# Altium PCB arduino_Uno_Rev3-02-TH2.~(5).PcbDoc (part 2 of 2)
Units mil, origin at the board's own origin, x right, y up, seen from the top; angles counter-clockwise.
Board outline 3492.03 x 2110.03 mil, 2 copper layers (Top Layer, Bottom Layer); 62 components, 73 nets, 317 pads, 75 vias.

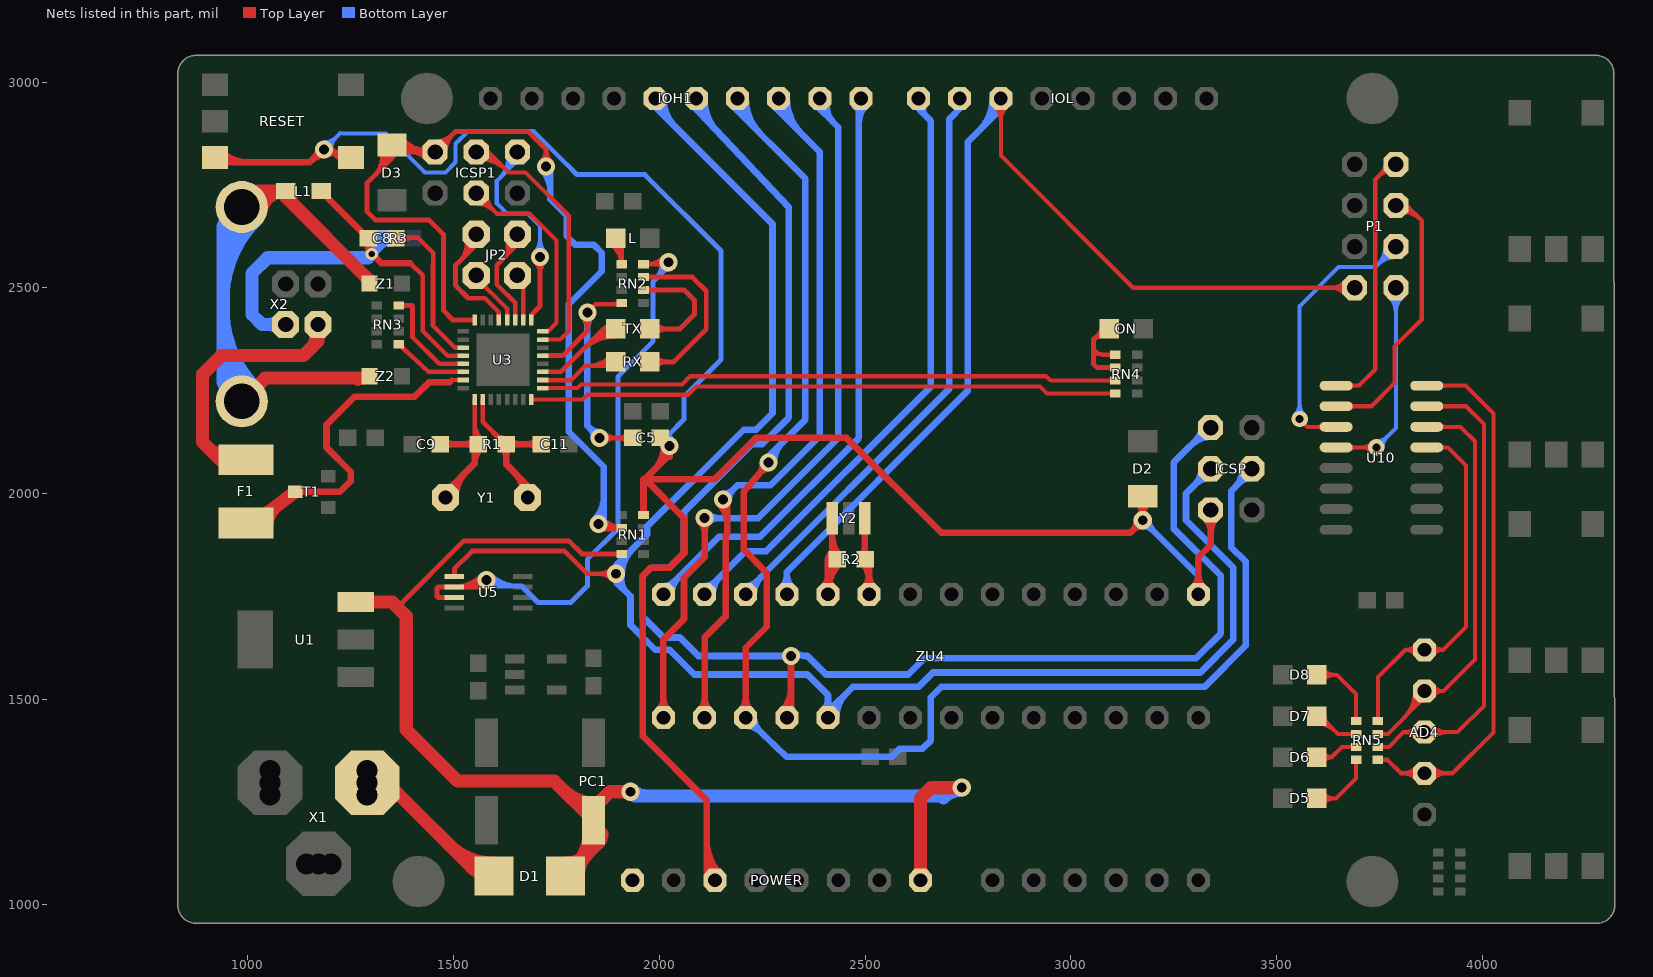
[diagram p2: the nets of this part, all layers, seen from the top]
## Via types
v1: diameter 44, hole 24, Top Layer to Bottom Layer, 62 vias
v2: diameter 30, hole 15, Top Layer to Bottom Layer, 10 vias
v3: diameter 40, hole 20, Top Layer to Bottom Layer, 2 vias
v4: diameter 50, hole 28, Top Layer to Bottom Layer, 1 vias

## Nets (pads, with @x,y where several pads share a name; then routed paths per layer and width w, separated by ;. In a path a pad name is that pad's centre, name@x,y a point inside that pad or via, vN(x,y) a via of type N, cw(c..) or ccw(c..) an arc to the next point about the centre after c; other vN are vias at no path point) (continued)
IO5: IOL.6 P1.7 ZU4.11 | length 3062.7
  Top Layer w10: IOL.6@2813.74,2943.74 cw(c2774.47,2904.47) 2830,2904.47 cw(c2885.53,2904.47) IOL.6@2846.26,2943.74 ; IOL.6@2820.81,2950.81 cw(c2798.62,2928.62) 2830,2928.62 cw(c2861.38,2928.62) IOL.6@2839.19,2950.81 ; IOL.6@2830,2960 2830,2821 3151,2500 P1.7@3690,2500 ; P1.7@3671.96,2481.96 ccw(c3628.41,2438.41) 3628.41,2500 ccw(c3628.41,2561.59) P1.7@3671.96,2518.04 ; P1.7@3679.03,2489.03 ccw(c3652.55,2462.55) 3652.55,2500 ccw(c3652.55,2537.45) P1.7@3679.03,2510.97
  Bottom Layer w16: ZU4.11@2295.86,1769.14 ccw(c2261.72,1803.28) 2310,1803.28 ccw(c2358.28,1803.28) ZU4.11@2324.14,1769.14 ; ZU4.11@2310,1755 2310,1810 2750,2250 2750,2855 2835,2940 IOL.6@2835,2960 ; 2778.18,2883.18 ccw(c2701.36,2960) IOL.6@2810,2960 ; 2805.49,2910.49 ccw(c2755.99,2960) IOL.6@2826,2960
IO6: IOL.7 ZU4.12 | length 1498.3
  Bottom Layer w16: ZU4.12@2210,1755 2210,1760 2705,2255 2705,2910 2735,2940 IOL.7@2735,2960 ; ZU4.12@2210,1775 ccw(c2210,1811.21) 2235.61,1785.61 ; ZU4.12@2230,1755 cw(c2290.36,1755) 2247.68,1797.68
IO7: IOL.8 ZU4.13 | length 1611.2
  Bottom Layer w16: ZU4.13@2110,1755 2110,1760 2210,1860 2260,1860 2660,2260 2660,2905 2635,2930 IOL.8@2635,2960 ; ZU4.13@2110,1775 ccw(c2110,1811.21) 2135.61,1785.61 ; ZU4.13@2130,1755 cw(c2190.36,1755) 2147.68,1797.68 ; IOL.8@2633.14,2957.53 ccw(c2649.31,2944.79) 2634.76,2930.24 ; IOL.8@2645.71,2947.63 ccw(c2663.57,2933.57) 2647.5,2917.5
IO8: IOH1.1 ZU4.14 | length 1636.2
  Bottom Layer w16: ZU4.14@2010,1755 2010,1760 2145,1895 2245,1895 2485,2135 2485,2950 2475,2940 IOH1.1@2475,2960 ; ZU4.14@2010,1775 ccw(c2010,1811.21) 2035.61,1785.61 ; ZU4.14@2030,1755 cw(c2090.36,1755) 2047.68,1797.68 ; IOH1.1@2475.86,2945.86 cw(c2453.79,2923.79) 2485,2923.79 ; 2485,2899.64 cw(c2550.36,2899.64) IOH1.1@2504.14,2945.86
IO9: IOH1.2 ZU4.15 | length 2060.7
  Top Layer w16: ZU4.15@1995.86,1469.14 ccw(c1961.72,1503.28) 2010,1503.28 ccw(c2058.28,1503.28) ZU4.15@2024.14,1469.14 ; ZU4.15@2010,1455 2010,1645 2060,1695 2060,1795 2110,1845 v1(2110,1940) ; v1@2100.1,1930.1 cw(c2076.2,1906.2) 2110,1906.2 cw(c2143.8,1906.2) v1@2119.9,1930.1
  Bottom Layer w16: v1(2110,1940) 2240,1940 2435,2135 2435,2890 2375,2950 IOH1.2@2375,2960 ; v1@2119.9,1930.1 cw(c2143.8,1906.2) 2143.8,1940 cw(c2143.8,1973.8) v1@2119.9,1949.9 ; IOH1.2@2393.84,2958.88 ccw(c2430.09,2948.31) 2403.39,2921.61 ; IOH1.2@2409.2,2954.4 ccw(c2459.68,2939.68) 2422.5,2902.5
L13: RN2.8 U5.6 U5.7 | length 1884.4
  Top Layer w12: U5.7@1501.85,1747.17 1462.83,1747.17 1460,1750 1460,1770 1462.76,1772.76 U5.6@1501.85,1772.76 ; 1530.07,1772.76 ccw(c1530.07,1838.08) v1@1577.12,1792.77 ; 1558.28,1772.76 ccw(c1558.28,1810.91) v1@1585.76,1784.45 ; v1@1568.47,1801.1 cw(c1501.85,1865.24) U5.6@1501.85,1772.76 ; v1(1580,1790) 1565,1775 1562.76,1772.76 U5.6@1501.85,1772.76 ; RN2.8@1961.57,2557.24 2027.24,2557.24 2032,2562 v1(2022,2562) ; RN2.8@1971.88,2557.24 ccw(c1971.88,2612.12) v1@2010.69,2573.31 ; 1994.86,2557.24 cw(c1994.86,2534.86) v1@2010.69,2550.69
  Bottom Layer w12: v1@1574.34,1784.34 ccw(c1596.9,1806.9) 1596.9,1775 ; v1(1580,1790) 1595,1775 1665,1775 1705,1735 1785,1735 1825,1775 1825,1840 1900,1915 1900,2285 1985,2370 1985,2515 2032,2562 v1(2022,2562) ; v1@1582.83,1792.83 ccw(c1625.87,1835.87) 1625.87,1775 ; v1@1591.31,1801.31 ccw(c1654.84,1864.84) 1654.84,1775 ; 1990,2520 ccw(c1951.21,2558.8) v1@2006.02,2561.28 ; 2009.25,2539.25 ccw(c1988.03,2560.46) v1@2018,2561.82 ; 2011.76,2541.76 cw(c2022,2531.51) v1@2022,2546
M8RXD: RN4.7 U3.9 | length 1426.8
  Top Layer w10: U3.9@1716.46,2256.1 1801.1,2256.1 1810,2265 2055,2265 2075,2285 2940,2285 2950.75,2274.25 RN4.7@3108.43,2274.25 ; RN4.7@3102.05,2270.83 ccw(c3093.79,2262.56) 3093.79,2274.25 ccw(c3093.79,2285.94) RN4.7@3102.05,2277.67
M8TXD: RN4.8 U3.8 | length 1458.1
  Top Layer w10: U3.8@1688.9,2228.54 1813.54,2228.54 1825,2240 2070,2240 2090,2260 2925,2260 2942.24,2242.76 RN4.8@3108.43,2242.76 ; RN4.8@3102.05,2239.34 ccw(c3093.79,2231.07) 3093.79,2242.76 ccw(c3093.79,2254.45) RN4.8@3102.05,2246.18
MISO: ICSP.1 IOH1.5 ZU4.18 | length 4098
  Top Layer w16: ZU4.18@2295.86,1469.14 ccw(c2237.57,1527.43) 2320,1527.43 ; ZU4.18@2307.17,1457.83 ccw(c2276.2,1488.8) 2320,1488.8 ; ZU4.18@2310,1455 2320,1465 v1(2320,1605)
  Bottom Layer w16: IOH1.5@2075,2950 IOH1.5@2075,2960 ; IOH1.5@2077.05,2947.82 2315,2695 2315,2185 2250,2120 2225,2120 2060,1955 2060,1855 2025,1820 1980,1820 1960,1800 1960,1700 2010,1650 2050,1650 2095,1605 v1(2320,1605) ; IOH1.5@2094,2959.88 ccw(c2164.32,2957.75) 2113.09,2909.53 ; IOH1.5@2109.99,2959.39 ccw(c2218.92,2956.09) 2139.56,2881.4 ; v1@2329.9,1614.9 ccw(c2353.8,1638.8) 2353.8,1605 ; 2360,1605 2405,1560 2605,1560 2645,1600 3305,1600 3365,1660 3365,1800 3250,1915 3250,2075 3333.03,2158.03 ICSP.1@3340,2160 ; 3293.03,2118.03 cw(c3340,2071.07) ICSP.1@3340,2137.49 ; 3305.11,2130.11 ccw(c3275.21,2160) ICSP.1@3317.49,2160
MISO2: ICSP1.1 U3.17 | length 921.2
  Top Layer w10: v1@1697.98,2562.98 cw(c1668.96,2533.96) 1710,2533.96 cw(c1751.04,2533.96) v1@1722.02,2562.98 ; 1710,2515 v1(1710,2575)
  Top Layer w11: U3.17@1688.9,2421.46 1688.9,2433.9 1695,2440 ; U3.17@1688.91,2429.73 cw(c1699.01,2429.73) 1691.87,2436.87
  Top Layer w12: 1695,2440 1710,2455 v1(1710,2575) ; v1@1698.69,2563.69 cw(c1671.37,2536.37) 1710,2536.37 cw(c1748.63,2536.37) v1@1721.31,2563.69
  Bottom Layer w10: 1615,2770 ccw(c1574.45,2810.56) ICSP1.1@1630.2,2824.01 ; 1627.61,2782.61 ccw(c1594.76,2815.46) ICSP1.1@1639.92,2826.36 ; 1640.22,2795.22 ccw(c1615.07,2820.36) ICSP1.1@1649.64,2828.71 ; ICSP1.1@1645.59,2800.59 cw(c1655,2791.18) ICSP1.1@1655,2804.49 ; ICSP1.1@1655,2830 1655,2810 1605,2760 1605,2705 1630,2680 1680,2680 1710,2650 v1(1710,2575) ; v1@1697.98,2587.02 ccw(c1668.96,2616.04) 1710,2616.04 ccw(c1751.04,2616.04) v1@1722.02,2587.02
MOSI: ICSP.4 IOH1.4 ZU4.17 | length 4138.3
  Top Layer w16: ZU4.17@2195.86,1469.14 ccw(c2161.72,1503.28) 2210,1503.28 ccw(c2258.28,1503.28) ZU4.17@2224.14,1469.14 ; ZU4.17@2210,1455 2210,1625 2261,1676 2261,1807 2205,1865 2205,2005 2215,2015 v1(2265,2075) ; v1@2251.06,2073.73 cw(c2217.4,2070.67) 2243.36,2049.03 cw(c2269.33,2027.4) v1@2266.27,2061.06
  Bottom Layer w15: 3390,1869 3390,2006
  Bottom Layer w16: IOH1.4@2175,2960 2175,2945 2355,2765 2355,2180 2265,2090 v1(2265,2075) ; IOH1.4@2178,2960 ccw(c2221.46,2960) 2190.73,2929.27 ; IOH1.4@2194,2960 ccw(c2276.08,2960) 2218.04,2901.96 ; ZU4.17@2210,1455 2310,1360 2565,1360 2585,1380 2640,1380 2660,1400 2660,1505 2685,1530 3325,1530 3425,1630 3425,1835 3390,1869 ; IOH1.4@2210,2960 ccw(c2330.71,2960) 2245.36,2874.64 ; ZU4.17@2210.51,1435.01 cw(c2211.75,1386.74) 2245.01,1421.74 cw(c2278.26,1456.75) ZU4.17@2229.99,1455.51 ; v1@2263,2075 cw(c2294.38,2075) 2272.19,2097.19 ; v1@2279,2075 cw(c2349.01,2075) 2299.51,2124.51 ; 3390,2006 3440.51,2055.51 ICSP.4@3440,2060 ; 3397.54,2013.39 ccw(c3350.98,2060.89) ICSP.4@3417.49,2060.23 ; 3409.83,2025.43 cw(c3439.35,1995.31) ICSP.4@3439.77,2037.49
MOSI2: ICSP1.4 U3.16 | length 649.4
  Top Layer w10: ICSP1.4@1555,2704.49 cw(c1555,2642.9) 1598.55,2686.45 cw(c1642.1,2730) ICSP1.4@1580.51,2730 ; ICSP1.4@1555,2714.49 cw(c1555,2677.04) 1581.48,2703.52 cw(c1607.96,2730) ICSP1.4@1570.51,2730 ; ICSP1.4@1555,2730 1605,2680 1685,2680 1750,2615 1750,2415 1728.9,2393.9 U3.16@1716.46,2393.9 ; U3.16@1724.73,2394.41 ccw(c1724.73,2405.72) 1732.72,2397.72
NetC5_1: C5.1 RN2.4 U3.13 | length 966
  Top Layer w10: v1(1825,2440) 1845,2460 RN2.4@1905.67,2460 ; 1887.12,2460 ccw(c1887.12,2481.11) RN2.4@1902.05,2466.18
  Top Layer w12: U3.13@1716.46,2334.84 1764.84,2334.84 1825,2395 v1(1825,2440) ; v1@1813.69,2428.69 cw(c1786.37,2401.37) 1825,2401.37 cw(c1863.63,2401.37) v1@1836.31,2428.69 ; v1@1866.31,2123.69 cw(c1893.63,2096.37) 1893.63,2135 cw(c1893.63,2173.63) v1@1866.31,2146.31 ; v1@1875,2135 C5.1@1935,2135 ; RN2.4@1905.67,2460 RN2.4@1908.43,2462.76 ; C5.1@1923.85,2125.1 ccw(c1899.95,2101.2) 1899.95,2135 ccw(c1899.95,2168.8) C5.1@1923.85,2144.9
  Top Layer w16: v1(1855,2135) v1@1875,2135
  Bottom Layer w16: v1@1815.1,2430.1 cw(c1791.2,2406.2) 1825,2406.2 cw(c1858.8,2406.2) v1@1834.9,2430.1 ; v1(1825,2440) 1825,2165 v1(1855,2135) ; v1@1841,2135 ccw(c1807.2,2135) 1831.1,2158.9 ccw(c1855,2182.8) v1@1855,2149
NetD5_C: D5.C RN5.8 | length 249.5
  Top Layer w10: D5.C@3598.34,1259 3645,1259 3693.43,1307.43 RN5.8@3693.43,1352.76 ; D5.C@3611.51,1245.83 cw(c3643.3,1214.04) 3643.3,1259 cw(c3643.3,1303.96) D5.C@3611.51,1272.17 ; RN5.8@3690.01,1349.34 cw(c3681.74,1341.07) 3693.43,1341.07 cw(c3705.12,1341.07) RN5.8@3696.85,1349.34
NetD6_C: D6.C RN5.7 | length 171.7
  Top Layer w10: D6.C@3598.34,1359 3634,1359 ; D6.C@3613.62,1348.36 cw(c3634,1334.17) 3634,1359 ; D6.C@3613.62,1369.64 ccw(c3634,1383.83) 3634,1359 ; RN5.7@3687.05,1380.83 ccw(c3678.79,1372.56) 3678.79,1384.25 ccw(c3678.79,1395.94) RN5.7@3687.05,1387.67 ; RN5.7@3693.43,1384.25 3659.25,1384.25 3634,1359
NetD7_C: D7.C RN5.6 | length 232.9
  Top Layer w10: D7.C@3598.34,1440.38 cw(c3598.34,1376.93) 3643.21,1421.79 ; D7.C@3598.34,1450.38 cw(c3598.34,1411.07) 3626.14,1438.86 ; D7.C@3598.34,1459 3606,1459 3649.25,1415.75 RN5.6@3693.43,1415.75 ; D7.C@3616.96,1459 ccw(c3643.43,1459) 3624.71,1440.29 ; RN5.6@3687.05,1412.33 ccw(c3678.79,1404.06) 3678.79,1415.75 ccw(c3678.79,1427.44) RN5.6@3687.05,1419.17
NetD8_C: D8.C RN5.5 | length 268.6
  Top Layer w10: D8.C@3598.34,1559 3647,1559 3693.43,1512.57 RN5.5@3693.43,1447.24 ; D8.C@3611.51,1545.83 cw(c3643.3,1514.04) 3643.3,1559 cw(c3643.3,1603.96) D8.C@3611.51,1572.17 ; RN5.5@3690.01,1450.66 ccw(c3681.74,1458.93) 3693.43,1458.93 ccw(c3705.12,1458.93) RN5.5@3696.85,1450.66
NetL_A: L.A RN2.1 | length 235.1
  Top Layer w11: L.A@1883.02,2605.33 cw(c1846.92,2555.53) RN2.1@1908.43,2555.53 ; L.A@1889.48,2614.23 cw(c1862.55,2577.09) 1908.43,2577.09 ; L.A@1893.66,2620 1885,2620 1908.43,2596.57 RN2.1@1908.43,2557.24 RN2.1@1900.76,2557.24 ; L.A@1895.94,2623.14 cw(c1878.18,2598.65) L.A@1908.43,2598.65 ; RN2.1@1905.36,2560.31 ccw(c1897.95,2567.72) 1908.43,2567.72 ccw(c1918.91,2567.72) RN2.1@1911.5,2560.31
NetON_A: ON.A RN4.5 RN4.6 | length 288
  Top Layer w12: ON.A@3076.43,2403.7 cw(c3034.83,2412.62) 3057.94,2376.9 cw(c3081.04,2341.17) ON.A@3089.96,2382.77 ; ON.A@3093.66,2400 3055,2375 3055,2350 ; RN4.6@3108.43,2305.75 3064.25,2305.75 3055,2315 3055,2350 ; RN4.5@3108.43,2337.24 3077.76,2337.24 3065,2340 3055,2350
NetP1_2: P1.2 U10.1 | length 762.2
  Top Layer w10: U10.1@3645,2262 3701,2262 3740,2301 3740,2763 3777,2800 P1.2@3790,2800 ; U10.1@3677.95,2257.05 cw(c3689.9,2245.1) 3689.9,2262 cw(c3689.9,2278.9) U10.1@3677.95,2266.95 ; 3747.91,2770.91 cw(c3781.93,2736.89) P1.2@3788.03,2784.61 ; 3755.64,2778.64 ccw(c3734.28,2800) P1.2@3764.49,2800 ; P1.2@3762.32,2785.32 cw(c3785.2,2762.43) P1.2@3789.3,2794.53
NetP1_4: P1.4 U10.2 | length 870.3
  Top Layer w10: U10.2@3645,2212 3731,2212 3787,2268 3787,2357 3853,2423 3853,2663 3816,2700 P1.4@3790,2700 ; U10.2@3677.95,2207.05 cw(c3689.9,2195.1) 3689.9,2212 cw(c3689.9,2228.9) U10.2@3677.95,2216.95 ; P1.4@3789.42,2704.45 cw(c3794.62,2664.73) 3822.94,2693.06 ; P1.4@3790.72,2694.53 cw(c3797.94,2639.35) 3837.29,2678.71 ; P1.4@3792.01,2684.62 cw(c3801.26,2613.97) 3851.65,2664.35
  Bottom Layer w10: P1.4@3765,2700 P1.4@3790,2700
NetP1_6: P1.6 U10.3 | length 921.3
  Top Layer w10: v3(3556,2181) 3575,2162 U10.3@3645,2162 ; U10.3@3612.05,2157.05 ccw(c3600.1,2145.1) 3600.1,2162 ccw(c3600.1,2178.9) U10.3@3612.05,2166.95
  Bottom Layer w10: v3@3545.39,2191.61 ccw(c3519.79,2217.21) 3556,2217.21 ccw(c3592.21,2217.21) v3@3566.61,2191.61 ; v3(3556,2181) 3555,2181 3556,2182 3556,2455 3651,2550 3740,2550 P1.6@3790,2600 P1.6@3774,2600 ; P1.6@3764.49,2600 cw(c3702.9,2600) 3746.45,2556.45 cw(c3790,2512.9) P1.6@3790,2574.49 ; P1.6@3774.49,2600 cw(c3737.04,2600) 3763.52,2573.52 cw(c3790,2547.04) P1.6@3790,2584.49
NetP1_8: P1.8 U10.4 | length 801.4
  Top Layer w10: U10.4@3645,2112 v3(3743,2112) ; U10.4@3677.95,2107.05 cw(c3689.9,2095.1) 3689.9,2112 cw(c3689.9,2128.9) U10.4@3677.95,2116.95 ; v3@3732.39,2101.39 ccw(c3706.79,2075.79) 3706.79,2112 ccw(c3706.79,2148.21) v3@3732.39,2122.61
  Bottom Layer w10: v3(3743,2112) 3790,2159 P1.8@3790,2500 ; v3@3743,2127 ccw(c3743,2163.21) 3768.61,2137.61 ccw(c3794.21,2112) v3@3758,2112 ; P1.8@3771.96,2481.96 cw(c3728.41,2438.41) 3790,2438.41 cw(c3851.59,2438.41) P1.8@3808.04,2481.96 ; P1.8@3779.03,2489.03 cw(c3752.55,2462.55) 3790,2462.55 cw(c3827.45,2462.55) P1.8@3800.97,2489.03
NetPOWER_1: POWER.1
NetRN2_6: RN2.6 TX.A | length 358.6
  Top Layer w12: RN2.6@1961.57,2494.25 2060.75,2494.25 2070,2485 2085,2470 2085,2435 2049.76,2399.76 1986.57,2399.76 TX.A@1976.34,2400 ; TX.A@1988.8,2387.54 cw(c2018.3,2358.04) 2018.3,2399.76 ; TX.A@1988.8,2412.46 ccw(c2019.46,2443.12) 2019.46,2399.76
NetRN2_7: RN2.7 RX.A | length 496.6
  Top Layer w12: RN2.7@1961.57,2525.75 2080.25,2525.75 2114,2492 2114,2399 2035,2320 RX.A@1976.34,2320 ; RX.A@1988.8,2307.54 cw(c2018.88,2277.46) 2018.88,2320 cw(c2018.88,2362.54) RX.A@1988.8,2332.46
OUT1: AD4.2 RN5.1 U10.16 | length 1618.1
  Top Layer w10: RN5.1@3746.57,1352.76 3770.24,1352.76 3803,1320 AD4.2@3860,1320 3928,1320 4027,1419 4027,2194 3959,2262 U10.16@3865,2262 ; RN5.1@3752.95,1349.34 cw(c3761.21,1341.07) 3761.21,1352.76 cw(c3761.21,1364.45) RN5.1@3752.95,1356.18 ; AD4.2@3843.74,1303.74 ccw(c3804.47,1264.47) 3804.47,1320 ccw(c3804.47,1375.53) AD4.2@3843.74,1336.26 ; AD4.2@3850.81,1310.81 ccw(c3828.62,1288.62) 3828.62,1320 ccw(c3828.62,1351.38) AD4.2@3850.81,1329.19 ; AD4.2@3869.19,1310.81 cw(c3891.38,1288.62) 3891.38,1320 cw(c3891.38,1351.38) AD4.2@3869.19,1329.19 ; AD4.2@3876.26,1303.74 cw(c3915.53,1264.47) 3915.53,1320 cw(c3915.53,1375.53) AD4.2@3876.26,1336.26 ; U10.16@3897.95,2257.05 cw(c3909.9,2245.1) 3909.9,2262 cw(c3909.9,2278.9) U10.16@3897.95,2266.95
OUT2: AD4.3 RN5.2 U10.15 | length 1441.5
  Top Layer w10: RN5.2@3746.57,1384.25 3773.25,1384.25 3809,1420 ; RN5.2@3752.95,1380.83 cw(c3761.21,1372.56) 3761.21,1384.25 cw(c3761.21,1395.94) RN5.2@3752.95,1387.67 ; AD4.3@3842.76,1404.78 ccw(c3809,1374.96) 3809,1420 ; AD4.3@3842.76,1435.22 cw(c3809,1465.04) 3809,1420 ; AD4.3@3850.26,1411.39 ccw(c3831.18,1394.54) 3831.18,1420 ccw(c3831.18,1445.46) AD4.3@3850.26,1428.61 ; U10.15@3865,2212 3961,2212 4004,2169 4004,1484 3940,1420 AD4.3@3860,1420 3809,1420 ; AD4.3@3869.19,1410.81 cw(c3891.38,1388.62) 3891.38,1420 cw(c3891.38,1451.38) AD4.3@3869.19,1429.19 ; AD4.3@3876.26,1403.74 cw(c3915.53,1364.47) 3915.53,1420 cw(c3915.53,1475.53) AD4.3@3876.26,1436.26 ; U10.15@3897.95,2207.05 cw(c3909.9,2195.1) 3909.9,2212 cw(c3909.9,2228.9) U10.15@3897.95,2216.95
OUT3: AD4.4 RN5.3 U10.14 | length 1264.7
  Top Layer w10: RN5.3@3746.57,1415.75 3770.75,1415.75 3860,1505 AD4.4@3860,1520 3906,1520 ; RN5.3@3752.95,1412.33 cw(c3761.21,1404.06) 3761.21,1415.75 cw(c3761.21,1427.44) RN5.3@3752.95,1419.17 ; 3810.13,1455.13 ccw(c3745.26,1520) AD4.4@3837,1520 ; 3827.2,1472.2 ccw(c3779.4,1520) AD4.4@3847,1520 ; 3844.27,1489.27 ccw(c3813.54,1520) AD4.4@3857,1520 ; 3846.34,1491.34 cw(c3860,1477.69) AD4.4@3860,1497 ; U10.14@3865,2162 3947,2162 3982,2127 3982,1596 3906,1520 ; AD4.4@3878.4,1506.2 cw(c3906,1485.5) 3906,1520 ; AD4.4@3878.4,1533.8 ccw(c3906,1554.5) 3906,1520 ; U10.14@3897.95,2157.05 cw(c3909.9,2145.1) 3909.9,2162 cw(c3909.9,2178.9) U10.14@3897.95,2166.95
OUT4: AD4.5 RN5.4 U10.13 | length 1050.5
  Top Layer w10: RN5.4@3743.15,1450.66 ccw(c3734.88,1458.93) 3746.57,1458.93 ccw(c3758.26,1458.93) RN5.4@3749.99,1450.66 ; RN5.4@3746.57,1447.24 3746.57,1553.57 3813,1620 ; AD4.5@3841.84,1605.89 ccw(c3813,1583.48) 3813,1620 ; AD4.5@3841.84,1634.11 cw(c3813,1656.52) 3813,1620 ; U10.13@3865,2112 3917,2112 3961,2068 3961,1676 3905,1620 ; AD4.5@3878.64,1606.53 cw(c3905,1587.48) 3905,1620 ; AD4.5@3878.64,1633.47 ccw(c3905,1652.52) 3905,1620 ; U10.13@3897.95,2107.05 cw(c3909.9,2095.1) 3909.9,2112 cw(c3909.9,2128.9) U10.13@3897.95,2116.95 ; 3813,1620 AD4.5@3860,1620 3905,1620
PB4: JP2.1 U3.18 | length 114.4
  Top Layer w11: U3.18@1669.21,2421.46 JP2.1@1669.21,2515.79
  Top Layer w12: JP2.1@1655,2530 JP2.1@1669.21,2515.79
PB5: JP2.3 U3.19 | length 392.5
  Top Layer w11: 1617.5,2567.5 ccw(c1581.85,2603.16) JP2.3@1629.18,2620.53 ; 1629.68,2579.68 ccw(c1599.66,2609.69) JP2.3@1639.51,2624.32 ; 1641.85,2591.85 ccw(c1617.47,2616.23) JP2.3@1649.84,2628.11 ; U3.19@1649.53,2421.46 1649.53,2463.47 1605,2508 1605,2555 JP2.3@1655,2605
  Top Layer w12: JP2.3@1655,2605 JP2.3@1655,2630
PB6: JP2.2 U3.20 | length 139.5
  Top Layer w10: JP2.2@1555,2524 1629.84,2449.16
  Top Layer w11: JP2.2@1555,2524 JP2.2@1555,2530 ; U3.20@1629.84,2421.46 1629.84,2449.16
PB7: JP2.4 U3.21 | length 439.7
  Top Layer w11: 1535,2475 1576,2475 1610.16,2440.84 U3.21@1610.16,2421.46
  Top Layer w12: 1517.5,2567.5 ccw(c1481.23,2603.77) JP2.4@1529.56,2620.95 ; 1530.93,2580.93 ccw(c1501.05,2610.82) JP2.4@1540.87,2624.97 ; 1535,2475 1505,2505 1505,2555 1555,2605 JP2.4@1555,2630 ; 1544.36,2594.36 ccw(c1520.86,2617.86) JP2.4@1552.17,2628.99
PWRIN: D1.A X1.2 | length 582
  Top Layer w32: X1.2@1295,1287 X1.2@1322,1260 ; X1.2@1360.5,1274.5 1545,1090 ; 1488.05,1146.95 ccw(c1598.39,1257.28) D1.A@1598.39,1101.24 ; 1542.68,1092.32 ccw(c1598.39,1148.03) D1.A@1598.39,1069.24 ; D1.A@1567.17,1068.72 ccw(c1545,1067.81) 1545,1090 ; D1.A@1598.39,1070 1578.39,1090 1545,1090
  Bottom Layer w32: X1.2@1295,1287 X1.2@1297,1285
RD+: RN3.4 U3.29 | length 259.8
  Top Layer w11: 1400,2380 1464.84,2315.16 U3.29@1523.54,2315.16
  Top Layer w12: RN3.4@1366.57,2457.24 1397.76,2457.24 1400,2455 1400,2380
RD-: RN3.1 U3.30 | length 198.2
  Top Layer w10: RN3.1@1366.57,2362.76 RN3.1@1367.72,2362.76
  Top Layer w11: RN3.1@1366.57,2362.76 1438.86,2295.47 U3.30@1523.54,2295.47 ; RN3.1@1373.86,2362.92 ccw(c1391.2,2363.54) 1379.38,2350.84
RESET: C5.2 D2.A ICSP.5 POWER.3 RESET.3 RESET.4 RN1.4 ZU4.1 | length 6501.8
  Top Layer w16: RESET.3@903,2805 1150,2805 1180,2835 v1(1185,2836.42) RESET.4@1250.35,2816.42 ; RESET.3@926.1,2818.94 ccw(c959.75,2852.58) 959.75,2805 ; RESET.3@937.41,2830.25 ccw(c998.37,2891.21) 998.37,2805 ; 1154.99,2809.99 cw(c1185,2779.98) v1@1185,2822.42 ; 1163.63,2818.63 ccw(c1145.84,2836.42) v1@1171,2836.42 ; v1@1191.57,2824.06 cw(c1207.43,2794.21) 1217.32,2826.53 cw(c1227.21,2858.85) v1@1197.36,2842.99 ; v1@1198.94,2832.15 cw(c1183.97,2783.24) RESET.4@1229.14,2807.24 ; v1@1204.26,2830.53 ccw(c1216.92,2871.92) RESET.4@1237.24,2833.69 ; RN1.4@1961.57,1947.24 1961.57,2035 ; 1986.96,2056.96 ccw(c1928.92,2115) C5.2@2011,2115 ; C5.2@2000.15,2123.55 cw(c1989.53,2089.71) 2025,2089.71 ; C5.2@2004.95,2138.82 cw(c1996.37,2111.5) v1@2025,2111.5 ; 2014.27,2084.27 ccw(c1983.54,2115) v1@2027,2115 ; v1(2025,2115) 2025,2095 1965,2035 ; 2115,1117.94 ccw(c2192.94,1117.94) POWER.3@2137.83,1062.83 ; 2115,1156.57 ccw(c2231.57,1156.57) POWER.3@2149.14,1074.14 ; POWER.3@2135,1060 2115,1080 2115,1255 1960,1410 1960,1800 1980,1820 2025,1820 2060,1855 2060,1940 1965,2035 ; v1@3161,1935 cw(c3127.2,1935) 3151.1,1911.1 cw(c3175,1887.2) v1@3175,1921 ; D2.A@3161.17,1979.24 cw(c3127.78,1945.85) 3175,1945.85 cw(c3222.22,1945.85) D2.A@3188.83,1979.24 ; v1@3165.1,1944.9 ccw(c3141.2,1968.8) 3175,1968.8 ccw(c3208.8,1968.8) v1@3184.9,1944.9 ; D2.A@3175,1993.07 v1(3175,1935) 3145,1905 2685,1905 2455,2135 2235,2135 2135,2035 1965,2035 ; ZU4.1@3295.86,1769.14 ccw(c3261.72,1803.28) 3310,1803.28 ccw(c3358.28,1803.28) ZU4.1@3324.14,1769.14 ; ZU4.1@3310,1755 3310,1845 3340.51,1875.51 ICSP.5@3340,1960 ; ICSP.5@3324.18,1943.99 cw(c3285.98,1905.32) 3340.33,1905.65 cw(c3394.68,1905.98) ICSP.5@3356.01,1944.18
  Bottom Layer w10: v1(1185,2836.42) 1224.58,2876 1230.58,2875 1335,2875 1430,2780 1480,2780 1505,2805 1505,2850 1536,2881 1694,2881 1775,2800 ; v1@1185,2853.42 ccw(c1185,2894.46) 1214.02,2865.44 ccw(c1243.04,2836.42) v1@1202,2836.42
  Bottom Layer w12: 1775,2800 1800,2775 1965,2775 2150,2590 2150,2325 2060,2235 2060,2180 2025,2145 ; v1@2016.09,2128.29 ccw(c2004.88,2145) 2025,2145 ; v1(2025,2115) 2025,2145 ; v1@2033.91,2128.29 cw(c2045.12,2145) 2025,2145
  Bottom Layer w16: v1@3175,1921 cw(c3175,1887.2) 3198.9,1911.1 cw(c3222.8,1935) v1@3189,1935 ; v1(3175,1935) 3310,1800 ; ZU4.1@3296.6,1769.85 ccw(c3269.38,1800) 3310,1800 ; ZU4.1@3310,1755 3310,1800 ; ZU4.1@3323.4,1769.85 cw(c3350.62,1800) 3310,1800
RESET2: D3.A ICSP1.5 RN1.6 U3.24 | length 3101.7
  Top Layer w12: 1309.9,2774.9 ccw(c1268.92,2815.88) D3.A@1322.28,2838.51 ; 1322.49,2787.49 ccw(c1286.6,2823.38) D3.A@1333.33,2843.2 ; 1335.07,2800.07 ccw(c1304.27,2830.87) D3.A@1344.37,2847.88 ; D3.A@1341.94,2826.93 cw(c1337.14,2815) 1350,2815 ; 1347.66,2812.66 ccw(c1321.94,2838.37) D3.A@1355.42,2852.57 ; D3.A@1356.15,2845.2 ccw(c1392.85,2881.91) 1392.85,2830 ; D3.A@1358.06,2826.93 ccw(c1362.86,2815) 1350,2815 ; D3.A@1364.63,2853.69 ccw(c1421.82,2910.88) 1421.82,2830 ; D3.A@1373.12,2862.17 ccw(c1450.79,2939.85) ICSP1.5@1450.79,2830 ; ICSP1.5@1437.67,2812.67 ccw(c1395.82,2770.82) 1395.82,2830 ccw(c1395.82,2889.18) ICSP1.5@1437.67,2847.33 ; ICSP1.5@1455,2854.51 ccw(c1455,2913.69) 1496.84,2871.84 ccw(c1538.69,2830) ICSP1.5@1479.51,2830 ; U3.24@1551.1,2421.46 1498.54,2421.46 1475,2445 1475,2630 1440,2665 1310,2665 1290,2685 1290,2755 1350,2815 ; v1@1713.69,2806.31 ccw(c1686.37,2833.63) 1725,2833.63 ccw(c1763.63,2833.63) v1@1736.31,2806.31 ; v1(1725,2795) 1725,2835 1680,2880 1505,2880 ICSP1.5@1455,2830 1366.93,2830 D3.A@1350,2846.93 1350,2815
  Top Layer w16: v1(1852,1926) 1852.25,1925.75 1865,1915 1865.75,1915.75 RN1.6@1908.43,1915.75 cw(c1908.43,1979.52) v1@1862.16,1935.63
  Bottom Layer w16: v1@1715.1,2785.1 cw(c1667.06,2737.06) 1735,2737.06 ; v1(1725,2795) 1735,2785 1735,2715 1775,2675 1775,2625 1795,2605 1840,2605 1860,2585 1860,2540 1780,2460 1780,2150 1865,2065 1865,1939 v1(1852,1926) ; v1@1842.1,1935.9 ccw(c1786.82,1991.18) 1865,1991.18 ; v1@1853.41,1924.59 ccw(c1825.44,1952.56) 1865,1952.56
RXLED: RX.C U3.10 | length 292.9
  Top Layer w11: U3.10@1716.46,2275.79 1785.79,2275.79 1820,2310 RX.C@1893.66,2310 ; 1825.77,2310 ccw(c1825.77,2387.89) RX.C@1880.85,2332.81 ; 1852.32,2310 ccw(c1852.32,2361.34) RX.C@1888.62,2325.04
SCK: ICSP.3 IOH1.6 U5.5 ZU4.19 | length 4813.5
  Top Layer w12: U5.5@1501.85,1798.35 1501.85,1816.85 1545,1860 1770,1860 1825,1805 v1(1895,1805) ; v1@1883.69,1793.69 ccw(c1856.37,1766.37) 1856.37,1805 ccw(c1856.37,1843.63) v1@1883.69,1816.31
  Bottom Layer w16: v1@1893,1805 cw(c1936.46,1805) 1905.73,1835.73 ; v1@1893.06,1805.49 ccw(c1919.09,1798.89) 1900.1,1779.9 ; v1@1908.57,1801.56 ccw(c1950.83,1790.83) 1920,1760 ; v1@1909,1805 cw(c1991.08,1805) 1933.04,1863.04 ; IOH1.6@1975,2960 1975,2955 2275,2655 2275,2195 2235,2155 2205,2155 1970,1920 1970,1900 1895,1825 v1(1895,1805) 1895,1785 1930,1750 1930,1680 1990,1620 2025,1620 2085,1560 2360,1560 2410,1510 ZU4.19@2410,1470 ; IOH1.6@1994,2960 ccw(c2051.94,2960) 2010.97,2919.03 ; IOH1.6@2010,2960 ccw(c2106.57,2960) 2038.28,2891.72 ; ZU4.19@2395.86,1469.14 ccw(c2361.72,1503.28) 2410,1503.28 ccw(c2458.28,1503.28) ZU4.19@2424.14,1469.14 ; ZU4.19@2410,1455 ZU4.19@2410,1470 ; ZU4.19@2414,1455 cw(c2459.87,1455) 2427.44,1487.44 ; ZU4.19@2430,1455 cw(c2514.5,1455) 2454.75,1514.75 ; ICSP.3@3317.49,2060 cw(c3263.14,2060) 3301.57,2021.57 cw(c3340,1983.14) ICSP.3@3340,2037.49 ; ICSP.3@3340,2060 3280,2000 3280,1935 3395,1820 3395,1645 3315,1565 2665,1565 2630,1530 2470,1530 ZU4.19@2410,1470
SCK2: ICSP1.3 U3.15 | length 843.4
  Top Layer w10: ICSP1.3@1555,2814.49 cw(c1555,2704.61) 1632.69,2782.31 ; ICSP1.3@1555,2824.49 cw(c1555,2738.76) 1615.62,2799.38 ; ICSP1.3@1555,2830 1585,2830 1635,2780 1675,2780 1780,2675 1780,2395 1759.21,2374.21 U3.15@1716.46,2374.21 ; ICSP1.3@1555,2834.49 cw(c1555,2772.9) 1598.55,2816.45
SS: IOH1.3 ZU4.16 | length 2099.5
  Top Layer w16: ZU4.16@2095.86,1469.14 ccw(c2061.72,1503.28) 2110,1503.28 ccw(c2158.28,1503.28) ZU4.16@2124.14,1469.14 ; ZU4.16@2110,1455 2110,1650 2161,1701 2161,1898 2165,1902 2165,1975 v1(2155,1985) ; v1@2145.1,1975.1 cw(c2097.06,1927.06) 2165,1927.06
  Bottom Layer w16: v1(2155,1985) 2190,2020 2270,2020 2390,2140 2390,2830 2275,2945 IOH1.3@2275,2960 ; v1@2155,1999 ccw(c2155,2032.8) 2178.9,2008.9 ccw(c2202.8,1985) v1@2169,1985 ; IOH1.3@2278,2960 ccw(c2321.46,2960) 2290.73,2929.27 ; IOH1.3@2294,2960 ccw(c2376.08,2960) 2318.04,2901.96 ; IOH1.3@2310,2960 ccw(c2430.71,2960) 2345.36,2874.64
TP_VUCAP: C8.1 U3.27 | length 432.6
  Top Layer w11: C8.1@1360,2621 1414,2621 1450,2585 1450,2555 ; C8.1@1371.5,2609.75 cw(c1398.67,2582.58) 1398.67,2621 ; C8.1@1371.5,2630.25 ccw(c1393.84,2652.59) 1393.84,2621 ; 1450,2408 1503.47,2354.53 U3.27@1523.54,2354.53
  Top Layer w12: 1450,2408 1450,2555
TXLED: TX.C U3.11 | length 554.1
  Top Layer w11: U3.11@1716.46,2295.47 1760.47,2295.47 1865,2400 ; 1813.8,2348.8 cw(c1893.66,2268.94) TX.C@1893.66,2381.88 ; 1832.58,2367.58 cw(c1893.66,2306.49) TX.C@1893.66,2392.88 ; 1850.67,2385.67 cw(c1866.56,2369.78) TX.C@1881.56,2386.51 ; 1851.35,2386.35 cw(c1893.66,2344.05) TX.C@1893.66,2403.88 ; 1858.88,2393.88 cw(c1874.32,2378.44) TX.C@1888.9,2394.7 ; 1867.1,2402.1 cw(c1882.09,2387.1) TX.C@1896.25,2402.89 ; TX.C@1877.29,2392.23 ccw(c1865,2386.4) 1865,2400 ; TX.C@1877.29,2407.77 cw(c1865,2413.6) 1865,2400 ; TX.C@1893.66,2400 1865,2400
UGND: C8.2 L1.1 R3.2 U3.28 X2.4 | length 1221.8
  Top Layer w11: 1425,2395 1485.16,2334.84 U3.28@1523.54,2334.84
  Top Layer w12: 1395,2560 1425,2530 1425,2395
  Top Layer w16: L1.1@1178.31,2731.69 1180.81,2731.69 C8.2@1292.5,2620 C8.2@1292.5,2613.5 ; C8.2@1289.25,2616.75 C8.2@1292.5,2613.5 ; v2@1301,2581 1292.5,2589.5 C8.2@1292.5,2613.5 ; v2@1301.5,2582.5 1324,2560 1395,2560
  Top Layer w24: L1.1@1178.31,2731.69 L1.1@1178.31,2735
  Top Layer w32: X2.4@1090.91,2410 X2.4@1091.69,2410.79
  Bottom Layer w24: X2.4@1090.91,2410 X2.4@1091.69,2410.79
  Bottom Layer w32: X2.4@1079.67,2398.77 ccw(c1050.65,2369.75) 1050.65,2410.79 ccw(c1050.65,2451.83) X2.4@1079.67,2422.81 ; X2.4@1091.69,2410.79 1034.21,2410.79 1010,2435 1010,2535 1048,2573 v2@1292,2573 ; v2(1301,2582) 1301,2588.5 R3.2@1332.5,2620
USBVCC: F1.1 T1.1 U3.31 | length 994.6
  Top Layer w0.31: F1.1@995,1928.23 F1.1@1011,1925
  Top Layer w10: 1495.79,2275.79 U3.31@1523.54,2275.79
  Top Layer w12: 1490,2270 1495.79,2275.79
  Top Layer w16: T1.1@1115,2004 1224,2004 1250,2030 1250,2053 1191,2112 1191,2167 1259,2235 1299,2235 ; T1.1@1122.3,1998.7 cw(c1135.11,1985.89) 1135.11,2004 cw(c1135.11,2022.11) T1.1@1122.3,2009.3 ; 1285,2235 1405,2235 1440,2270 1490,2270
  Top Layer w32: F1.1@971.77,1925 1011,1925 T1.1@1115,2004 ; F1.1@1027.42,1949.43 ccw(c1031.83,1981.65) F1.1@1051.49,1955.76 ; F1.1@1045.73,1925.33 cw(c1115.9,1915.75) 1073.06,1972.14
USHIELD: L1.2 X2.P$1 X2.P$2 Z1.2 Z2.2 | length 2497.1
  Top Layer w24: 1267.82,2272.82 cw(c1284.1,2256.53) Z2.2@1292.75,2277.88 ; Z2.2@1288.83,2288.59 cw(c1275.63,2295.56) 1275.63,2280.63 ; Z2.2@1289.62,2289.79 cw(c1270.63,2304.89) 1270.63,2280.63 1275.63,2280.63 ; Z2.2@1295.63,2285 1280,2285 1275.63,2280.63
  Top Layer w32: X2.P$2@985,2223.78 1041.85,2280.63 1270.63,2280.63 ; X2.P$1@985,2696.22 1023.78,2735 L1.2@1091.69,2735 ; X2.P$1@999.96,2692.99 cw(c1052.03,2681.73) 1052.03,2735 ; X2.P$1@1031.24,2686.22 cw(c1091.69,2673.16) L1.2@1091.69,2735 ; L1.2@1099.31,2735 ccw(c1150.76,2735) 1114.38,2698.62 ; Z1.2@1284.13,2528.87 cw(c1265.26,2510) Z1.2@1291.95,2510 ; Z1.2@1295.63,2510 Z1.2@1295.63,2517.37 ; Z1.2@1295.63,2518.37 Z1.2@1295.63,2517.37 ; L1.2@1091.69,2735 1091.69,2721.31 Z1.2@1295.63,2517.37 ; Z2.2@1276.18,2280.63 ccw(c1276.18,2304.45) 1293.02,2287.61 cw(c1276.18,2304.45) Z2.2@1276.18,2280.63
  Bottom Layer w32: 940,2292.12 ccw(c1053.34,2292.12) X2.P$2@973.2,2211.98 ; 940,2369.37 ccw(c1130.59,2369.37) X2.P$2@995.82,2234.6 ; 940,2446.63 ccw(c1207.85,2446.63) X2.P$2@1018.45,2257.23 ; 940,2473.37 cw(c1207.85,2473.37) X2.P$1@1018.45,2662.77 ; 940,2550.63 cw(c1130.59,2550.63) X2.P$1@995.82,2685.4 ; 940,2627.88 cw(c1053.34,2627.88) X2.P$1@973.2,2708.02 ; X2.P$2@985,2223.78 985,2225 940,2270 940,2650 985,2695 X2.P$1@985,2696.22
VIN: D1.C PC1.+ POWER.8 RN1.8 U1.3 | length 3533.2
  Top Layer w12: 1363.56,1723.56 1525,1885 1780,1885 1812.24,1852.76 RN1.8@1908.43,1852.76
  Top Layer w32: U1.3@1262,1736 1351.11,1736 1352.19,1734.92 1385,1702.11 1385,1426 1510,1301 1744.51,1301 PC1.+@1840,1205.51 ; 1766.5,1279.01 ccw(c1840,1352.51) 1840,1248.57 ccw(c1840,1281.31) PC1.+@1863.16,1258.16 ; D1.C@1771.61,1070 1840,1138.39 PC1.+@1840,1205.51 ; D1.C@1771.61,1101.24 ccw(c1771.61,1176.67) 1824.95,1123.34 ccw(c1878.28,1070) D1.C@1802.85,1070 ; D1.C@1795.08,1093.47 ccw(c1714.53,1174.01) PC1.+@1828.44,1174.01 ; PC1.+@1831.83,1165.84 cw(c1812.09,1146.11) 1840,1146.11 cw(c1867.91,1146.11) PC1.+@1848.17,1165.84 ; PC1.+@1849.7,1148.1 ccw(c1823.79,1174.01) PC1.+@1860.44,1174.01 ; v1(1930,1275) 1880,1275 1840,1235 PC1.+@1840,1205.51 ; POWER.8@2626.51,1068.49 ccw(c2606.03,1088.97) 2635,1088.97 ccw(c2663.97,1088.97) POWER.8@2643.49,1068.49 ; POWER.8@2635,1060 2635,1260 2660,1285 v1(2735,1285)
  Bottom Layer w32: v1(1930,1275) 1940,1265 2695,1265 2715,1285 v1(2735,1285) ; v1@1934.24,1279.24 ccw(c1968.63,1313.63) 1968.63,1265 ; 2690.62,1260.62 cw(c2735,1216.23) v1@2735,1279
XT1: C9.2 R1.1 U3.1 Y1.2 | length 732.8
  Top Layer w10: R1.1@1550,2125 1551.1,2126.1 R1.1@1555,2130
  Top Layer w11: R1.1@1551.1,2131.1 U3.1@1551.1,2228.54 ; 1551.1,2146.92 ccw(c1585.67,2146.92) R1.1@1561.22,2122.47 ; 1551.1,2173.47 ccw(c1612.22,2173.47) R1.1@1569,2130.25
  Top Layer w12: R1.1@1550,2125 R1.1@1551.1,2131.1
  Top Layer w16: C9.2@1467.5,2120 R1.1@1551.1,2120 ; C9.2@1477.24,2111.51 cw(c1497.72,2091.03) 1497.72,2120 cw(c1497.72,2148.97) C9.2@1477.24,2128.49 ; Y1.2@1480,1990 1480,2002 1551.1,2073.1 R1.1@1551.1,2120 ; Y1.2@1480,2015 ccw(c1480,2046.38) 1502.19,2024.19 ; Y1.2@1485,2010 Y1.2@1500,2010 ; Y1.2@1489,1990 cw(c1539.7,1990) 1503.85,2025.85 ; Y1.2@1505,1990 cw(c1594.33,1990) 1531.16,2053.16 ; R1.1@1550.26,2111.51 ccw(c1529.78,2091.03) 1529.78,2120 ccw(c1529.78,2148.97) R1.1@1550.26,2128.49 ; 1551.1,2072.56 cw(c1606.19,2072.56) R1.1@1567.24,2111.51 ; R1.1@1551.1,2131.1 R1.1@1551.1,2120 ; R1.1@1560,2120 R1.1@1551.1,2120
XT2: C11.2 R1.2 U3.2 Y1.1 | length 691.1
  Top Layer w11: 1570.79,2174.21 U3.2@1570.79,2228.54
  Top Layer w12: 1570.79,2174.21 R1.2@1620,2125 ; 1600.22,2144.78 ccw(c1626.25,2170.82) R1.2@1626.25,2134 ; 1603.23,2141.77 cw(c1581.47,2120) R1.2@1612.25,2120
  Top Layer w16: R1.2@1619.01,2111.51 cw(c1598.53,2091.03) 1627.5,2091.03 cw(c1656.47,2091.03) R1.2@1635.99,2111.51 ; R1.2@1637.24,2111.51 cw(c1657.72,2091.03) 1657.72,2120 cw(c1657.72,2148.97) R1.2@1637.24,2128.49 ; 1644.13,2054.87 cw(c1579.26,1990) Y1.1@1671,1990 ; 1671.44,2027.56 cw(c1633.89,1990) Y1.1@1687,1990 ; Y1.1@1675,2015 1680,2010 Y1.1@1680,1990 1680,2019 1627.5,2071.5 R1.2@1627.5,2120 C11.2@1712.5,2120 ; C11.2@1702.76,2111.51 ccw(c1682.28,2091.03) 1682.28,2120 ccw(c1682.28,2148.97) C11.2@1702.76,2128.49
XTAL1: R2.1 Y2.3 ZU4.9 | length 382.5
  Top Layer w16: R2.1@2490.26,1848.49 ccw(c2468.28,1870.47) 2499.37,1870.47 ; R2.1@2492.76,1831.51 cw(c2451.16,1789.91) 2510,1789.91 ; Y2.3@2495.28,1910.32 cw(c2485.42,1900.46) 2499.37,1900.46 cw(c2513.32,1900.46) Y2.3@2503.46,1910.32 ; ZU4.9@2495.86,1769.14 ccw(c2461.72,1803.28) 2510,1803.28 ccw(c2558.28,1803.28) ZU4.9@2524.14,1769.14 ; 2499.37,1867.47 ccw(c2526.22,1867.47) R2.1@2507.24,1848.49 ; Y2.3@2499.37,1940 2499.37,1859.37 2495,1855 2510,1840 ZU4.9@2510,1755
XTAL2: R2.2 Y2.1 ZU4.10 | length 490.2
  Top Layer w16: ZU4.10@2395.86,1769.14 ccw(c2361.72,1803.28) 2410,1803.28 ccw(c2458.28,1803.28) ZU4.10@2424.14,1769.14 ; ZU4.10@2410,1755 2410,1840 2425,1855 2420.63,1859.37 Y2.1@2420.63,1940 ; ZU4.10@2410,1759.73 cw(c2511.52,1759.73) R2.2@2439.74,1831.51 ; 2410,1798.35 cw(c2472.9,1798.35) R2.2@2428.42,1842.83 ; 2410,1836.98 cw(c2434.27,1836.98) R2.2@2417.11,1854.14 ; Y2.1@2416.54,1910.32 cw(c2406.68,1900.46) 2420.63,1900.46 cw(c2434.58,1900.46) Y2.1@2424.72,1910.32 ; 2420.63,1894.61 ccw(c2485.86,1894.61) R2.2@2439.74,1848.49
XUSB: F1.2 X2.1 | length 809.3
  Top Layer w32: 906.12,2108.88 ccw(c936.51,2139.26) F1.2@955.84,2100.88 ; F1.2@995,2081.77 933.23,2081.77 890,2125 890,2290 935,2335 1135,2335 1170,2370 ; 1155.18,2355.18 ccw(c1131.61,2378.75) X2.1@1157.32,2399.97 ; X2.1@1158.34,2398.84 cw(c1129.57,2370.43) 1170,2370 ; X2.1@1170.43,2410.79 1170,2370 ; X2.1@1182.27,2398.59 ccw(c1210.43,2369.58) 1170,2370
  Bottom Layer w12: X2.1@1170,2410.35 X2.1@1170.43,2410.79
pads on no net: RESET.5 RN3.2 RN3.3 RN3.6 RN3.7 S1.5 S2.5 S3.5 S4.5 U2.4 U3.5 U3.6 U3.7 U3.12 U3.14 U3.22 U3.23 U3.25 U3.26 U10.5 U10.6 U10.7 U10.10 U10.11 U10.12 X1.4 X1.5 X1.6 X1.7 X1.8 X1.9

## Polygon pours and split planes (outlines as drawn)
GND on Top Layer "Top Layer-No Net" (solid, remove dead copper): 805,3126 805,914 4379,914 4396,897 4366,927 4366,3139 800,3139
GND on Bottom Layer "Top Layer-No Net" (solid, remove dead copper): 754.51,3100.74 723.51,3069.74 723.51,901.74 4316.51,901.74 4363.51,948.74 4332.51,979.74 4332.51,3126.74

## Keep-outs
Keep-Out Layer:
  lines w10: 4276,3060 cw(c4276,3020.63) 4315.37,3020.63 ; 4276.63,960 874.37,960 cw(c874.37,999.37) 835,999.37 835,3020.63 cw(c874.37,3020.63) 874.37,3060 4277,3060 ; 4277.63,960 ccw(c4277.63,999.37) 4317,999.37 ; 4315.13,3020.63 4317,994

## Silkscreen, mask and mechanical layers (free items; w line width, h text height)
Top Overlay:
  circle w10: c1705,2880 r10
  lines w12: 1985,2780 2030,2735 2350,2735 ; 2770,2735 3090,2735 3135,2780 ; 3215,2780 3235,2800 3255,2780 3225,2780 3240,2790 ; 3320,2805 3360,2805 3340,2785 3325,2800 3345,2800 ; 3340,2790 3340,2795 ; 3200,2775 3270,2775 3235,2810 3200,2775 ; 3305,2810 3375,2810 3340,2775 3305,2810
  text "AREF" at 1741.17,2895.52 h56 r270
  text "GND" at 1845.75,2894.52 h56 r270
  text "13" at 1945,2890 h56 r270
  text "12" at 2045,2890 h56 r270
  text "11" at 2145,2890 h56 r270
  text "10" at 2245,2890 h56 r270
  text "9" at 2345,2890 h56 r270
  text "8" at 2445,2890 h56 r270
  text "7" at 2605,2890 h56 r270
  text "6" at 2705,2890 h56 r270
  text "5" at 2805,2890 h56 r270
  text "4" at 2905,2890 h56 r270
  text "3" at 3005,2890 h56 r270
  text "2" at 3105,2890 h56 r270
  text "1" at 3205,2890 h56 r270
  text "0" at 3305,2890 h56 r270
  text "#" at 2395,2795 h44 r90
  text "#" at 2760,2795 h44 r90
  text "#" at 2855,2795 h44 r90
  text "#" at 3055,2795 h44 r90
  text "#" at 2200,2745 h44 r90
  text "#" at 2300,2745 h44 r90
  text "DIGITAL" at 2376.43,2708.59 h66
  text "TX" at 3265,2660 h56 r90
  text "RX" at 3365,2660 h56 r90
  text "L" at 2020,2601 h50
  text "Arduino" at 2435,2460 h110
  text "ON" at 3226,2378 h50
  text "TX" at 2015,2365 h56
  text "UNO" at 2435,2310 h125
  text "RX" at 2026,2290 h56
  text "cy-seu" at 2417,2170 h100
  text "O4" at 3936,1592 h56
  text "O3" at 3935,1489 h56
  text "O2" at 3935,1393 h56
  text "POWER" at 2205,1302 h56
  text "ANALOG IN" at 2825,1290 h56
  text "O1" at 3940,1290 h56
  text "5V" at 3936,1191 h56
  text "IOREF" at 2060,1135 h56 r90
  text "RESET" at 2145,1135 h56 r90
  text "5V" at 2360,1135 h56 r90
  text "A4" at 3255,1135 h56 r90
  text "A0" at 2836,1134 h56 r90
  text "3V3" at 2255,1130 h56 r90
  text "GND" at 2460,1130 h56 r90
  text "GND" at 2560,1130 h56 r90
  text "A1" at 2960,1130 h56 r90
  text "A2" at 3060,1130 h56 r90
  text "A3" at 3155,1130 h56 r90
  text "A5" at 3355,1130 h56 r90
  text "VIN" at 2655,1125 h56 r90
Bottom Overlay:
  text "cy-seu" at 2894,2190 h100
